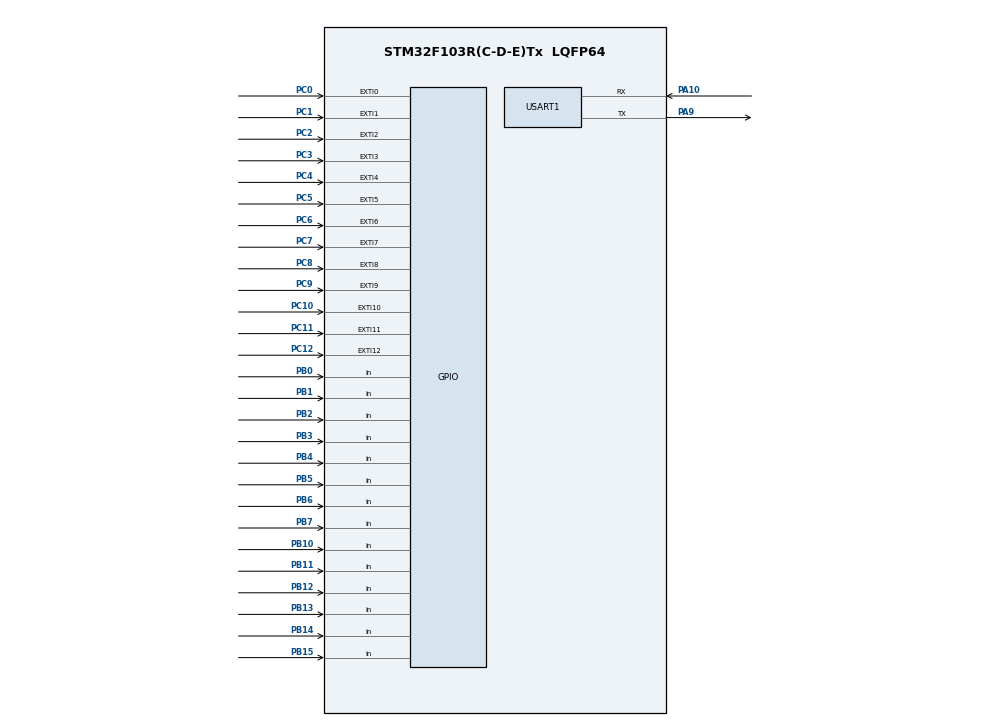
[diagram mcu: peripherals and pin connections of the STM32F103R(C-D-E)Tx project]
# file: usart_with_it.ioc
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Mcu.Family=STM32F1
Mcu.Name=STM32F103R(C-D-E)Tx
Mcu.Package=LQFP64
NVIC.EXTI0_IRQn=true\:1\:0\:true\:false\:true\:true\:true
NVIC.EXTI15_10_IRQn=true\:7\:0\:true\:false\:true\:true\:true
NVIC.EXTI1_IRQn=true\:2\:0\:true\:false\:true\:true\:true
NVIC.EXTI2_IRQn=true\:3\:0\:true\:false\:true\:true\:true
NVIC.EXTI3_IRQn=true\:4\:0\:true\:false\:true\:true\:true
NVIC.EXTI4_IRQn=true\:5\:0\:true\:false\:true\:true\:true
NVIC.EXTI9_5_IRQn=true\:6\:0\:true\:false\:true\:true\:true
NVIC.PriorityGroup=NVIC_PRIORITYGROUP_4
NVIC.USART1_IRQn=true\:0\:0\:false\:false\:true\:true\:true
PA10.Mode=Asynchronous
PA10.Signal=USART1_RX
PA9.Mode=Asynchronous
PA9.Signal=USART1_TX
PB0.GPIO_PuPd=GPIO_PULLDOWN
PB0.Signal=GPIO_Input
PB1.GPIO_PuPd=GPIO_PULLDOWN
PB1.Signal=GPIO_Input
PB10.GPIO_PuPd=GPIO_PULLDOWN
PB10.Signal=GPIO_Input
PB11.GPIO_PuPd=GPIO_PULLDOWN
PB11.Signal=GPIO_Input
PB12.GPIO_PuPd=GPIO_PULLDOWN
PB12.Signal=GPIO_Input
PB13.GPIO_PuPd=GPIO_PULLDOWN
PB13.Signal=GPIO_Input
PB14.GPIO_PuPd=GPIO_PULLDOWN
PB14.Signal=GPIO_Input
PB15.GPIO_PuPd=GPIO_PULLDOWN
PB15.Signal=GPIO_Input
PB2.GPIO_PuPd=GPIO_PULLDOWN
PB2.Signal=GPIO_Input
PB3.GPIO_PuPd=GPIO_PULLDOWN
PB3.Signal=GPIO_Input
PB4.GPIO_PuPd=GPIO_PULLDOWN
PB4.Signal=GPIO_Input
PB5.GPIO_PuPd=GPIO_PULLDOWN
PB5.Signal=GPIO_Input
PB6.GPIO_PuPd=GPIO_PULLDOWN
PB6.Signal=GPIO_Input
PB7.GPIO_PuPd=GPIO_PULLDOWN
PB7.Signal=GPIO_Input
PC0.GPIO_ModeDefaultEXTI=GPIO_MODE_IT_RISING
PC0.GPIO_PuPd=GPIO_PULLDOWN
PC0.Signal=GPXTI0
PC1.GPIO_ModeDefaultEXTI=GPIO_MODE_IT_FALLING
PC1.GPIO_PuPd=GPIO_PULLUP
PC1.Signal=GPXTI1
PC10.GPIO_ModeDefaultEXTI=GPIO_MODE_IT_FALLING
PC10.GPIO_PuPd=GPIO_PULLUP
PC10.Signal=GPXTI10
PC11.GPIO_ModeDefaultEXTI=GPIO_MODE_IT_FALLING
PC11.GPIO_PuPd=GPIO_PULLUP
PC11.Signal=GPXTI11
PC12.GPIO_ModeDefaultEXTI=GPIO_MODE_IT_FALLING
PC12.GPIO_PuPd=GPIO_PULLUP
PC12.Signal=GPXTI12
PC2.GPIO_ModeDefaultEXTI=GPIO_MODE_IT_FALLING
PC2.GPIO_PuPd=GPIO_PULLUP
PC2.Signal=GPXTI2
PC3.GPIO_ModeDefaultEXTI=GPIO_MODE_IT_FALLING
PC3.GPIO_PuPd=GPIO_PULLUP
PC3.Signal=GPXTI3
PC4.GPIO_ModeDefaultEXTI=GPIO_MODE_IT_FALLING
PC4.GPIO_PuPd=GPIO_PULLUP
PC4.Signal=GPXTI4
PC5.GPIO_ModeDefaultEXTI=GPIO_MODE_IT_FALLING
PC5.GPIO_PuPd=GPIO_PULLUP
PC5.Signal=GPXTI5
PC6.GPIO_ModeDefaultEXTI=GPIO_MODE_IT_FALLING
PC6.GPIO_PuPd=GPIO_PULLUP
PC6.Signal=GPXTI6
PC7.GPIO_ModeDefaultEXTI=GPIO_MODE_IT_FALLING
PC7.GPIO_PuPd=GPIO_PULLUP
PC7.Signal=GPXTI7
PC8.GPIO_ModeDefaultEXTI=GPIO_MODE_IT_FALLING
PC8.GPIO_PuPd=GPIO_PULLUP
PC8.Signal=GPXTI8
PC9.GPIO_ModeDefaultEXTI=GPIO_MODE_IT_FALLING
PC9.GPIO_PuPd=GPIO_PULLUP
PC9.Signal=GPXTI9
ProjectManager.HeapSize=0x200
ProjectManager.StackSize=0x400
ProjectManager.TargetToolchain=MDK-ARM V5.27
RCC.APB1Freq_Value=8000000
RCC.APB2Freq_Value=8000000
USART1.VirtualMode=VM_ASYNC
VP_SYS_VS_ND.Mode=No_Debug
board=custom

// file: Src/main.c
/* USER CODE BEGIN Header */
/**
  ******************************************************************************
  * @file           : main.c
  * @brief          : Main program body
  ******************************************************************************
  * @attention
  *
  * <h2><center>&copy; Copyright (c) 2020 STMicroelectronics.
  * All rights reserved.</center></h2>
  *
  * This software component is licensed by ST under BSD 3-Clause license,
  * the "License"; You may not use this file except in compliance with the
  * License. You may obtain a copy of the License at:
  *                        opensource.org/licenses/BSD-3-Clause
  *
  ******************************************************************************
  */
/* USER CODE END Header */

#include "main.h"

/* USER CODE BEGIN Includes */
#include "stdio.h"
#include "stmflash.h"
/* USER CODE END Includes */

/* USER CODE BEGIN PTD */
#include <string.h>

#define RXBUFFERSIZE 256     //???????
//要写入到STM32 FLASH的字符串数组
unsigned int TEXT_Buffer[12];
#define SIZE sizeof(TEXT_Buffer)	 	//数组长度
unsigned int  datatemp[SIZE];
#define FLASH_SAVE_ADDR  0X08020000 	//设置FLASH 保存地址(必须为偶数，且其值要大于本代码所占用FLASH的大小+0X08000000)

unsigned int count[12];
unsigned char RxBuffer[RXBUFFERSIZE];   //????
uint8_t aRxBuffer;			//??????
uint8_t Uart1_Rx_Cnt = 0;		//??????
uint8_t IDH=0,IDL=0;
unsigned int ID=0;
/* USER CODE END PTD */

UART_HandleTypeDef huart1;

void SystemClock_Config(void);
static void MX_GPIO_Init(void);
static void MX_USART1_UART_Init(void);

/* USER CODE BEGIN 0 */

/**
  * ????: ???c???printf?DEBUG_USARTx
  * ????: ?
  * ? ? ?: ?
  * ?    ?:?
  */
int fputc(int ch, FILE *f)
{
  HAL_UART_Transmit(&huart1, (uint8_t *)&ch, 1, 0xffff);
  return ch;
}

/**
  * ????: ???c???getchar,scanf?DEBUG_USARTx
  * ????: ?
  * ? ? ?: ?
  * ?    ?:?
  */
int fgetc(FILE *f)
{
  uint8_t ch = 0;
  HAL_UART_Receive(&huart1, &ch, 1, 0xffff);
  return ch;
}

unsigned int  GPIO_ReCMD(GPIO_TypeDef* GPIOx)
{
	uint16_t cmd;
   cmd= GPIOx->IDR;
	return cmd;
}
/* USER CODE END 0 */

int main(void)
{

  /* MCU Configuration--------------------------------------------------------*/

  /* Reset of all peripherals, Initializes the Flash interface and the Systick. */
  HAL_Init();

  /* Configure the system clock */
  SystemClock_Config();

  /* Initialize all configured peripherals */
  MX_GPIO_Init();
  MX_USART1_UART_Init();
  /* USER CODE BEGIN 2 */
HAL_UART_Receive_IT(&huart1, (uint8_t *)&aRxBuffer, 1);

STMFLASH_Read(FLASH_SAVE_ADDR,(u16*)TEXT_Buffer,SIZE);
if(TEXT_Buffer[0]==0xffffffff&&TEXT_Buffer[1]==0xffffffff&&TEXT_Buffer[2]==0xffffffff&&TEXT_Buffer[3]==0xffffffff)
{//printf("的确是0xffffffff");
TEXT_Buffer[0]=0x00;TEXT_Buffer[1]=0x00;TEXT_Buffer[2]=0x00;TEXT_Buffer[3]=0x00;TEXT_Buffer[4]=0x00;TEXT_Buffer[5]=0x00;TEXT_Buffer[6]=0x00;
	TEXT_Buffer[7]=0x00;TEXT_Buffer[8]=0x00;TEXT_Buffer[9]=0x00;TEXT_Buffer[10]=0x00;TEXT_Buffer[11]=0x00;

	STMFLASH_Write(FLASH_SAVE_ADDR,(u16*)TEXT_Buffer,SIZE);
}
//STMFLASH_Read(FLASH_SAVE_ADDR,(u16*)datatemp,SIZE);

  /* USER CODE END 2 */

  /* Infinite loop */
  while (1)
  {
    HAL_Delay(4000);
		ID=GPIO_ReCMD(GPIOB);
		IDH=ID>>8;
		IDL=ID;
//		char a=0xff;
//		HAL_UART_Transmit(&huart1, (uint8_t *)&TEXT_Buffer[0], 1,0xFFFF);
//		HAL_UART_Transmit(&huart1, (uint8_t *)&TEXT_Buffer[1], 1,0xFFFF);
//		HAL_UART_Transmit(&huart1, (uint8_t *)&TEXT_Buffer[2], 1,0xFFFF);
//		HAL_UART_Transmit(&huart1, (uint8_t *)&TEXT_Buffer[3], 1,0xFFFF);
//		HAL_UART_Transmit(&huart1, (uint8_t *)&TEXT_Buffer[4], 1,0xFFFF);
//		HAL_UART_Transmit(&huart1, 0x00, 1,0xFFFF);
//		HAL_UART_Transmit(&huart1, (uint8_t *)0x00, 1,0xFFFF);
//		printf("%x\r\n",GPIO_ReCMD(GPIOB));
		//printf("%x",TEXT_Buffer[0]);
//		//GPIO_ReCMD(GPIOB);
//		for(int i=0;i<1;i++)
//		//printf("NO.%d count is %d\r\n",i+1,count[i]);
//		printf("1\r\n");
//		STMFLASH_Read(FLASH_SAVE_ADDR,(u16*)datatemp,SIZE);
//		printf("%s",datatemp);
  }
}

void SystemClock_Config(void)
{
  RCC_OscInitTypeDef RCC_OscInitStruct = {0};
  RCC_ClkInitTypeDef RCC_ClkInitStruct = {0};

  /** Initializes the CPU, AHB and APB busses clocks
  */
  RCC_OscInitStruct.OscillatorType = RCC_OSCILLATORTYPE_HSI;
  RCC_OscInitStruct.HSIState = RCC_HSI_ON;
  RCC_OscInitStruct.HSICalibrationValue = RCC_HSICALIBRATION_DEFAULT;
  RCC_OscInitStruct.PLL.PLLState = RCC_PLL_NONE;
  if (HAL_RCC_OscConfig(&RCC_OscInitStruct) != HAL_OK)
  {
    Error_Handler();
  }
  /** Initializes the CPU, AHB and APB busses clocks
  */
  RCC_ClkInitStruct.ClockType = RCC_CLOCKTYPE_HCLK|RCC_CLOCKTYPE_SYSCLK
                              |RCC_CLOCKTYPE_PCLK1|RCC_CLOCKTYPE_PCLK2;
  RCC_ClkInitStruct.SYSCLKSource = RCC_SYSCLKSOURCE_HSI;
  RCC_ClkInitStruct.AHBCLKDivider = RCC_SYSCLK_DIV1;
  RCC_ClkInitStruct.APB1CLKDivider = RCC_HCLK_DIV1;
  RCC_ClkInitStruct.APB2CLKDivider = RCC_HCLK_DIV1;

  if (HAL_RCC_ClockConfig(&RCC_ClkInitStruct, FLASH_LATENCY_0) != HAL_OK)
  {
    Error_Handler();
  }
}

static void MX_USART1_UART_Init(void)
{

  huart1.Instance = USART1;
  huart1.Init.BaudRate = 9600;
  huart1.Init.WordLength = UART_WORDLENGTH_8B;
  huart1.Init.StopBits = UART_STOPBITS_1;
  huart1.Init.Parity = UART_PARITY_NONE;
  huart1.Init.Mode = UART_MODE_TX_RX;
  huart1.Init.HwFlowCtl = UART_HWCONTROL_NONE;
  huart1.Init.OverSampling = UART_OVERSAMPLING_16;
  if (HAL_UART_Init(&huart1) != HAL_OK)
  {
    Error_Handler();
  }

}

static void MX_GPIO_Init(void)
{
  GPIO_InitTypeDef GPIO_InitStruct = {0};

  /* GPIO Ports Clock Enable */
  __HAL_RCC_GPIOC_CLK_ENABLE();
  __HAL_RCC_GPIOB_CLK_ENABLE();
  __HAL_RCC_GPIOA_CLK_ENABLE();

  /*Configure GPIO pin : PC0 */
  GPIO_InitStruct.Pin = GPIO_PIN_0;
  GPIO_InitStruct.Mode = GPIO_MODE_IT_RISING;
  GPIO_InitStruct.Pull = GPIO_PULLDOWN;
  HAL_GPIO_Init(GPIOC, &GPIO_InitStruct);

  /*Configure GPIO pins : PC1 PC2 PC3 PC4
                           PC5 PC6 PC7 PC8
                           PC9 PC10 PC11 PC12 */
  GPIO_InitStruct.Pin = GPIO_PIN_1|GPIO_PIN_2|GPIO_PIN_3|GPIO_PIN_4
                          |GPIO_PIN_5|GPIO_PIN_6|GPIO_PIN_7|GPIO_PIN_8
                          |GPIO_PIN_9|GPIO_PIN_10|GPIO_PIN_11|GPIO_PIN_12;
  GPIO_InitStruct.Mode = GPIO_MODE_IT_FALLING;
  GPIO_InitStruct.Pull = GPIO_PULLUP;
  HAL_GPIO_Init(GPIOC, &GPIO_InitStruct);

  /*Configure GPIO pins : PB0 PB1 PB2 PB10
                           PB11 PB12 PB13 PB14
                           PB15 PB3 PB4 PB5
                           PB6 PB7 */
  GPIO_InitStruct.Pin = GPIO_PIN_0|GPIO_PIN_1|GPIO_PIN_2|GPIO_PIN_10
                          |GPIO_PIN_11|GPIO_PIN_12|GPIO_PIN_13|GPIO_PIN_14
                          |GPIO_PIN_15|GPIO_PIN_3|GPIO_PIN_4|GPIO_PIN_5
                          |GPIO_PIN_6|GPIO_PIN_7|GPIO_PIN_8|GPIO_PIN_9;
  GPIO_InitStruct.Mode = GPIO_MODE_INPUT;
  GPIO_InitStruct.Pull = GPIO_PULLDOWN;
  HAL_GPIO_Init(GPIOB, &GPIO_InitStruct);

  /* EXTI interrupt init*/
  HAL_NVIC_SetPriority(EXTI0_IRQn, 1, 0);
  HAL_NVIC_EnableIRQ(EXTI0_IRQn);

  HAL_NVIC_SetPriority(EXTI1_IRQn, 2, 0);
  HAL_NVIC_EnableIRQ(EXTI1_IRQn);

  HAL_NVIC_SetPriority(EXTI2_IRQn, 3, 0);
  HAL_NVIC_EnableIRQ(EXTI2_IRQn);

  HAL_NVIC_SetPriority(EXTI3_IRQn, 4, 0);
  HAL_NVIC_EnableIRQ(EXTI3_IRQn);

  HAL_NVIC_SetPriority(EXTI4_IRQn, 5, 0);
  HAL_NVIC_EnableIRQ(EXTI4_IRQn);

  HAL_NVIC_SetPriority(EXTI9_5_IRQn, 6, 0);
  HAL_NVIC_EnableIRQ(EXTI9_5_IRQn);

  HAL_NVIC_SetPriority(EXTI15_10_IRQn, 7, 0);
  HAL_NVIC_EnableIRQ(EXTI15_10_IRQn);

}

/* USER CODE BEGIN 4 */

/* USER CODE BEGIN 4 */

void HAL_UART_RxCpltCallback(UART_HandleTypeDef *huart)
{
  /* Prevent unused argument(s) compilation warning */
  UNUSED(huart);
  /* NOTE: This function Should not be modified, when the callback is needed,
           the HAL_UART_TxCpltCallback could be implemented in the user file
   */

	if(Uart1_Rx_Cnt >= 255)  //????
	{
		Uart1_Rx_Cnt = 0;
		memset(RxBuffer,0x00,sizeof(RxBuffer));
		HAL_UART_Transmit(&huart1, (uint8_t *)"????", 10,0xFFFF);

	}
	else
	{
		RxBuffer[Uart1_Rx_Cnt++] = aRxBuffer;   //??????

		if((RxBuffer[Uart1_Rx_Cnt-1] == 0xAA)&&(RxBuffer[Uart1_Rx_Cnt-2] == 0xAA)&&(RxBuffer[Uart1_Rx_Cnt-3] ==0xAA)&&(RxBuffer[Uart1_Rx_Cnt-4] == 0xAA)) //?????
		{
			STMFLASH_Read(FLASH_SAVE_ADDR,(u16*)datatemp,SIZE);
			char a=0xAA,b=0x01;//b用痈窀柃
		//	IDH=0x01;
			//IDL=0x04;//改这个ID

			//16进制发送部分
			 //printf("!!!!");printf("$$$$");printf("#####");

			HAL_UART_Transmit(&huart1, (uint8_t *)&b, 1,0xFFFF);
			HAL_UART_Transmit(&huart1, (uint8_t *)&b, 1,0xFFFF);
			HAL_UART_Transmit(&huart1, (uint8_t *)&b, 1,0xFFFF);
			HAL_UART_Transmit(&huart1, (uint8_t *)&b, 1,0xFFFF);
			HAL_UART_Transmit(&huart1, (uint8_t *)&b, 1,0xFFFF);
			HAL_UART_Transmit(&huart1, (uint8_t *)&b, 1,0xFFFF);
			HAL_UART_Transmit(&huart1, (uint8_t *)&b, 1,0xFFFF);
			HAL_UART_Transmit(&huart1, (uint8_t *)&b, 1,0xFFFF);

			HAL_UART_Transmit(&huart1, (uint8_t *)&IDH, 1,0xFFFF);
			HAL_UART_Transmit(&huart1, (uint8_t *)&IDL, 1,0xFFFF);
						HAL_UART_Transmit(&huart1, (uint8_t *)&b, 1,0xFFFF);
			for(int i=0;i<12;i++)//这里是16进制发送
			{

			HAL_UART_Transmit(&huart1, (uint8_t *)&datatemp[i], 1,0xFFFF);
			}
			//16进制发送部分

//			//字符串发送部分
//			//printf("%d",IDH);
//			 printf("!!!!");
//			printf("%6d",IDL);
//			printf(",");
//			//printf("%d",0x00);
//			printf("%d",0x01);
//			//printf(",");
//			for(int i=0;i<12;i++)//这里是16进制发送
//			{
//      printf(",");
//			printf("%d",datatemp[i]);
//			}
//			printf("$$$$");
//			//字符串进制发送部分
//

//			for(int i=0;i<12;i++)
//			{
//			HAL_UART_Transmit(&huart1, (uint8_t *)&TEXT_Buffer[i], 1,0xFFFF);
//			}
			//printf("%d",datatemp[0]);
//			HAL_UART_Transmit(&huart1, (uint8_t *)&RxBuffer, Uart1_Rx_Cnt,0xFFFF); //??????????
//            while(HAL_UART_GetState(&huart1) == HAL_UART_STATE_BUSY_TX);//??UART????
			Uart1_Rx_Cnt = 0;
			memset(RxBuffer,0x00,sizeof(RxBuffer)); //????
		}
	}

	HAL_UART_Receive_IT(&huart1, (uint8_t *)&aRxBuffer, 1);   //???????
}

void HAL_GPIO_EXTI_Callback(uint16_t GPIO_Pin)
{
	//	printf("interrupt\r\n");
	//////////////////////////////////////////////////////
	if(GPIO_Pin == GPIO_PIN_0)
	{
		HAL_Delay(1);//如果发生中断  是需要复位flash中的数据。
	//	printf("ZHONGDUANLE");
	//	if(HAL_GPIO_ReadPin(GPIOC,GPIO_PIN_0)==GPIO_PIN_RESET)
		{
			//printf("的确是0xffffffff");
  TEXT_Buffer[0]=0x00;TEXT_Buffer[1]=0x00;TEXT_Buffer[2]=0x00;TEXT_Buffer[3]=0x00;TEXT_Buffer[4]=0x00;TEXT_Buffer[5]=0x00;TEXT_Buffer[6]=0x00;
	TEXT_Buffer[7]=0x00;TEXT_Buffer[8]=0x00;TEXT_Buffer[9]=0x00;TEXT_Buffer[10]=0x00;TEXT_Buffer[11]=0x00;
	count[0]=0x00;count[1]=0x00;count[2]=0x00;count[3]=0x00;count[4]=0x00;count[5]=0x00;count[6]=0x00;
	count[7]=0x00;count[8]=0x00;count[9]=0x00;count[10]=0x00;count[11]=0x00;
			datatemp[0]=0x00;datatemp[1]=0x00;datatemp[2]=0x00;datatemp[3]=0x00;datatemp[4]=0x00;datatemp[5]=0x00;datatemp[6]=0x00;
	datatemp[7]=0x00;datatemp[8]=0x00;datatemp[9]=0x00;datatemp[10]=0x00;datatemp[11]=0x00;
	STMFLASH_Write(FLASH_SAVE_ADDR,(u16*)TEXT_Buffer,SIZE);

		}
	}
	////////////////////////////////////////////
	if(GPIO_Pin == GPIO_PIN_1)
	{
	//	HAL_Delay(1);
		if(HAL_GPIO_ReadPin(GPIOC,GPIO_PIN_1)==GPIO_PIN_RESET)
		{
			count[0]++;
			TEXT_Buffer[0]++;
		}
	}
	if(GPIO_Pin == GPIO_PIN_2)
	{
	//	HAL_Delay(1);
		if(HAL_GPIO_ReadPin(GPIOC,GPIO_PIN_2)==GPIO_PIN_RESET)
		{
			count[1]++;TEXT_Buffer[1]++;
		}
	}
	if(GPIO_Pin == GPIO_PIN_3)
	{
	//	HAL_Delay(1);
		if(HAL_GPIO_ReadPin(GPIOC,GPIO_PIN_3)==GPIO_PIN_RESET)
		{
			count[2]++;TEXT_Buffer[2]++;
		}
	}
	if(GPIO_Pin == GPIO_PIN_4)
	{
	//	HAL_Delay(1);
		if(HAL_GPIO_ReadPin(GPIOC,GPIO_PIN_4)==GPIO_PIN_RESET)
		{
			count[3]++;TEXT_Buffer[3]++;
		}
	}
	if(GPIO_Pin == GPIO_PIN_5)
	{
	//	HAL_Delay(1);
		if(HAL_GPIO_ReadPin(GPIOC,GPIO_PIN_5)==GPIO_PIN_RESET)
		{
			count[4]++;TEXT_Buffer[4]++;
		}
	}
	if(GPIO_Pin == GPIO_PIN_6)
	{
	//	HAL_Delay(1);
		if(HAL_GPIO_ReadPin(GPIOC,GPIO_PIN_6)==GPIO_PIN_RESET)
		{
			count[5]++;TEXT_Buffer[5]++;
		}
	}
	if(GPIO_Pin == GPIO_PIN_7)
	{
	//	HAL_Delay(1);
		if(HAL_GPIO_ReadPin(GPIOC,GPIO_PIN_7)==GPIO_PIN_RESET)
		{
			count[6]++;TEXT_Buffer[6]++;
		}
	}
	if(GPIO_Pin == GPIO_PIN_8)
	{
	//	HAL_Delay(1);
		if(HAL_GPIO_ReadPin(GPIOC,GPIO_PIN_8)==GPIO_PIN_RESET)
		{
			count[7]++;TEXT_Buffer[7]++;
		}
	}
	if(GPIO_Pin == GPIO_PIN_9)
	{
	//	HAL_Delay(1);
		if(HAL_GPIO_ReadPin(GPIOC,GPIO_PIN_9)==GPIO_PIN_RESET)
		{
			count[8]++;TEXT_Buffer[8]++;
		}
	}
	if(GPIO_Pin == GPIO_PIN_10)
	{
//		HAL_Delay(1);
		if(HAL_GPIO_ReadPin(GPIOC,GPIO_PIN_10)==GPIO_PIN_RESET)
		{
			count[9]++;TEXT_Buffer[9]++;
		}
	}
	if(GPIO_Pin == GPIO_PIN_11)
	{
//		HAL_Delay(1);
		if(HAL_GPIO_ReadPin(GPIOC,GPIO_PIN_11)==GPIO_PIN_RESET)
		{
			count[10]++;TEXT_Buffer[10]++;
		}
	}
	if(GPIO_Pin == GPIO_PIN_12)
	{
//		HAL_Delay(1);
		if(HAL_GPIO_ReadPin(GPIOC,GPIO_PIN_12)==GPIO_PIN_RESET)
		{
			count[11]++;TEXT_Buffer[11]++;
		}
	}

	STMFLASH_Write(FLASH_SAVE_ADDR,(u16*)TEXT_Buffer,SIZE);// jishu hou  bao cun  flash
}
/* USER CODE END 4 */

void Error_Handler(void)
{
}

/************************ (C) COPYRIGHT STMicroelectronics *****END OF FILE****/
